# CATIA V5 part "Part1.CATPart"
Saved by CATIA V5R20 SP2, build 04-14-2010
Part number: Part1
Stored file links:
  C:\Documents and Settings\Administrator\My Documents\Hobi_dokumenti\CAD_CNC\Clap_CATIA\Part1.CATPart

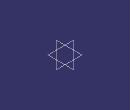
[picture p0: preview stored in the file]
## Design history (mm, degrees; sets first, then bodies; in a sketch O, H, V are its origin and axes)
Body1 (main body)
